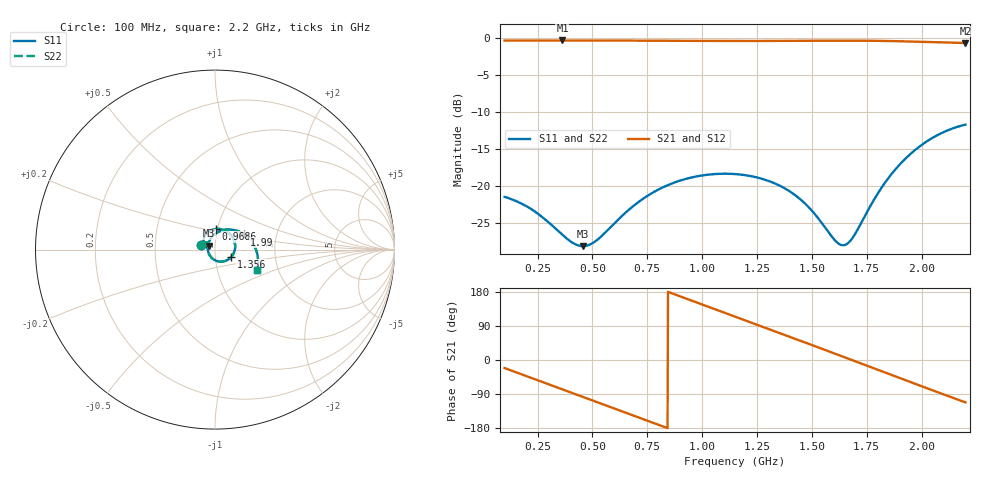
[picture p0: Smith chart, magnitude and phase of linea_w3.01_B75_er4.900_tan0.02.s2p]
! Chirptenna · simulación 3D de una microstrip de dos puertos (S12 = S21, S22 = S11 por simetría)
# HZ S RI R 50
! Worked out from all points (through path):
!   1101 points, 100 MHz to 2.2 GHz, reference 50 ohm
!   highest |S21| = -0.33 dB at 363.5 MHz (marker M1); lowest = -0.7 dB at 2.2 GHz (marker M2)
!   group delay of S21, straight-line fit = 596 ps
!   lowest |S11| = -28.2 dB at 457 MHz (marker M3), VSWR 1.08, Z = 46.8 + j1.99 ohm
!   |S11| at or under -10 dB: start of sweep to end of sweep
!   |S22| runs from -28.2 to -11.7 dB; largest |S21 - S12| = 0
!   S11 on the Smith chart (normalised r, x): 100 MHz: 0.85, +0.04; 968.6 MHz: 0.98, +0.23; 1.356 GHz: 1.20, -0.10; 1.99 GHz: 1.37, +0.24; 2.2 GHz: 1.55, -0.38
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1e8  -0.0803 0.0251  0.8966 -0.3493  0.8966 -0.3493  -0.0803 0.0251
2.431818e8  -0.0517 0.0412  0.5955 -0.7564  0.5955 -0.7564  -0.0517 0.0412
3.634545e8  -0.0332 0.0326  0.2093 -0.9399  0.2093 -0.9399  -0.0332 0.0326
4.512727e8  -0.0324 0.0219  -0.104 -0.9571  -0.104 -0.9571  -0.0324 0.0219
4.57e8  -0.0327 0.0213  -0.1244 -0.9547  -0.1244 -0.9547  -0.0327 0.0213
6.116364e8  -0.0535 0.0221  -0.6241 -0.7316  -0.6241 -0.7316  -0.0535 0.0221
7.09e8  -0.0636 0.0441  -0.8421 -0.4617  -0.8421 -0.4617  -0.0636 0.0441
8.006364e8  -0.0573 0.0748  -0.9468 -0.1527  -0.9468 -0.1527  -0.0573 0.0748
8.846364e8  -0.0334 0.1012  -0.9467 0.146  -0.9467 0.146  -0.0334 0.1012
9.686364e8  0.00542 0.1151  -0.8548 0.4298  -0.8548 0.4298  0.00542 0.1151
1.064091e9  0.0566 0.1061  -0.6511 0.6996  -0.6511 0.6996  0.0566 0.1061
1.15e9  0.0946 0.0739  -0.3979 0.8683  -0.3979 0.8683  0.0946 0.0739
1.253091e9  0.1124 0.0161  -0.0435 0.9542  -0.0435 0.9542  0.1124 0.0161
1.356182e9  0.0915 -0.0397  0.3183 0.9017  0.3183 0.9017  0.0915 -0.0397
1.501273e9  0.0169 -0.0655  0.7413 0.6079  0.7413 0.6079  0.0169 -0.0655
1.608182e9  -0.0312 -0.0287  0.9221 0.2677  0.9221 0.2677  -0.0312 -0.0287
1.654e9  -0.0399 -0.00161  0.9546 0.104  0.9546 0.104  -0.0399 -0.00161
1.751364e9  -0.0239 0.0618  0.9261 -0.2488  0.9261 -0.2488  -0.0239 0.0618
1.850636e9  0.0394 0.1065  0.765 -0.571  0.765 -0.571  0.0394 0.1065
1.99e9  0.1633 0.0847  0.3684 -0.8687  0.3684 -0.8687  0.1633 0.0847
2.093091e9  0.228 0.00146  0.0139 -0.9339  0.0139 -0.9339  0.228 0.00146
2.2e9  0.2334 -0.1129  -0.3441 -0.8598  -0.3441 -0.8598  0.2334 -0.1129
